VERSION 5.8 ;
BUSBITCHARS "[]" ;
DIVIDERCHAR "/" ;
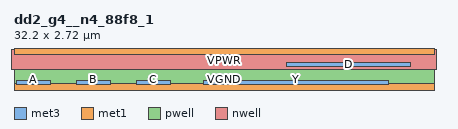
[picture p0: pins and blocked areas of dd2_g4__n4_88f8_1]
MACRO dd2_g4__n4_88f8_1
  CLASS CORE ;
  ORIGIN 0 0 ;
  SIZE 32.200 BY 2.720 ;
  SYMMETRY X Y ;
  SITE unithd ;
  PIN A
    DIRECTION INPUT ;
    USE SIGNAL ;
    ANTENNAGATEAREA 0.213000 ;
    PORT
      LAYER met3 ;
        RECT 0.185 0.175 2.815 0.505 ;
    END
  END A
  PIN B
    DIRECTION INPUT ;
    USE SIGNAL ;
    ANTENNAGATEAREA 0.213000 ;
    PORT
      LAYER met3 ;
        RECT 4.785 0.175 7.415 0.505 ;
    END
  END B
  PIN C
    DIRECTION INPUT ;
    USE SIGNAL ;
    ANTENNAGATEAREA 0.213000 ;
    PORT
      LAYER met3 ;
        RECT 9.385 0.175 12.015 0.505 ;
    END
  END C
  PIN D
    DIRECTION INPUT ;
    USE SIGNAL ;
    ANTENNAGATEAREA 0.213000 ;
    PORT
      LAYER met3 ;
        RECT 20.885 1.535 30.415 1.865 ;
    END
  END D
  PIN VGND
    DIRECTION INOUT ;
    USE GROUND ;
    SHAPE ABUTMENT ;
    PORT
      LAYER met1 ;
        RECT 0.000 -0.240 32.200 0.240 ;
    END
  END VGND
  PIN VNB
    DIRECTION INOUT ;
    USE GROUND ;
    PORT
      LAYER pwell ;
        RECT 0.000 0.000 32.200 1.305 ;
    END
  END VNB
  PIN VPB
    DIRECTION INOUT ;
    USE POWER ;
    PORT
      LAYER nwell ;
        RECT -0.190 1.305 32.390 2.910 ;
    END
  END VPB
  PIN VPWR
    DIRECTION INOUT ;
    USE POWER ;
    SHAPE ABUTMENT ;
    PORT
      LAYER met1 ;
        RECT 0.000 2.480 32.200 2.960 ;
    END
  END VPWR
  PIN Y
    DIRECTION OUTPUT ;
    USE SIGNAL ;
    ANTENNADIFFAREA 0.965600 ;
    PORT
      LAYER met3 ;
        RECT 14.560 0.175 28.690 0.505 ;
    END
  END Y
  OBS
    LAYER li1 ;
      RECT 0.000 -0.085 32.200 0.085 ;
      RECT 0.000 2.635 32.200 2.805 ;
      RECT 22.190 0.085 22.360 0.255 ;
      RECT 19.810 0.255 20.140 0.635 ;
      RECT 22.110 0.255 22.440 0.635 ;
      RECT 17.010 0.255 17.340 0.380 ;
      RECT 16.860 0.380 17.340 0.710 ;
      RECT 17.510 0.255 17.840 0.380 ;
      RECT 17.510 0.380 17.880 0.710 ;
      RECT 19.310 0.255 19.640 0.380 ;
      RECT 19.160 0.380 19.640 0.710 ;
      RECT 21.610 0.255 21.940 0.380 ;
      RECT 21.460 0.380 21.940 0.710 ;
      RECT 16.265 0.380 16.615 0.710 ;
      RECT 16.265 0.710 16.435 1.075 ;
      RECT 16.265 1.075 17.440 1.315 ;
      RECT 18.565 0.380 18.915 0.710 ;
      RECT 18.565 0.710 18.735 1.075 ;
      RECT 18.565 1.075 19.740 1.315 ;
      RECT 20.865 0.380 21.215 0.710 ;
      RECT 20.865 0.710 21.035 1.075 ;
      RECT 20.865 1.075 22.040 1.315 ;
      RECT 23.165 0.380 23.515 0.710 ;
      RECT 23.165 0.710 23.335 1.075 ;
      RECT 23.165 1.075 24.340 1.315 ;
      RECT 25.465 0.380 25.815 0.710 ;
      RECT 25.465 0.710 25.635 1.075 ;
      RECT 25.465 1.075 26.640 1.315 ;
      RECT 27.765 0.380 28.115 0.710 ;
      RECT 27.765 0.710 27.935 1.075 ;
      RECT 27.765 1.075 28.940 1.315 ;
      RECT 30.065 0.380 30.415 0.710 ;
      RECT 30.065 0.710 30.235 1.075 ;
      RECT 30.065 1.075 31.240 1.315 ;
      RECT 23.910 1.505 24.240 2.010 ;
      RECT 23.760 2.010 24.240 2.340 ;
      RECT 23.910 2.340 24.240 2.465 ;
      RECT 24.410 1.505 24.740 2.010 ;
      RECT 24.410 2.010 24.780 2.340 ;
      RECT 24.410 2.340 24.740 2.465 ;
      RECT 26.210 1.505 26.540 2.010 ;
      RECT 26.060 2.010 26.540 2.340 ;
      RECT 26.210 2.340 26.540 2.465 ;
      RECT 28.510 1.505 28.840 2.010 ;
      RECT 28.360 2.010 28.840 2.340 ;
      RECT 28.510 2.340 28.840 2.465 ;
      RECT 29.010 1.505 29.340 2.010 ;
      RECT 29.010 2.010 29.380 2.340 ;
      RECT 29.010 2.340 29.340 2.465 ;
      RECT 30.810 1.505 31.140 2.010 ;
      RECT 30.660 2.010 31.140 2.340 ;
      RECT 30.810 2.340 31.140 2.465 ;
      RECT 26.710 1.505 27.040 2.465 ;
      RECT 31.310 1.505 31.640 2.465 ;
      RECT 26.790 2.465 26.960 2.635 ;
      RECT 31.390 2.465 31.560 2.635 ;
      RECT 19.890 0.085 20.060 0.255 ;
      RECT 15.210 0.380 15.580 0.710 ;
      RECT 6.090 0.085 6.260 0.255 ;
      RECT 1.410 0.255 1.740 0.635 ;
      RECT 6.010 0.255 6.340 0.635 ;
      RECT 10.610 0.255 10.940 0.635 ;
      RECT 10.690 0.085 10.860 0.255 ;
      RECT 1.490 0.085 1.660 0.255 ;
      RECT 0.910 0.255 1.240 0.380 ;
      RECT 0.760 0.380 1.240 0.710 ;
      RECT 0.165 0.380 0.515 0.710 ;
      RECT 0.165 0.710 0.335 1.075 ;
      RECT 0.165 1.075 1.340 1.315 ;
      RECT 2.465 0.380 2.815 0.710 ;
      RECT 2.465 0.710 2.635 1.075 ;
      RECT 3.210 1.505 3.540 2.010 ;
      RECT 3.060 2.010 3.540 2.340 ;
      RECT 3.210 2.340 3.540 2.465 ;
      RECT 7.810 1.505 8.140 2.010 ;
      RECT 7.660 2.010 8.140 2.340 ;
      RECT 7.810 2.340 8.140 2.465 ;
      RECT 12.410 1.505 12.740 2.010 ;
      RECT 12.260 2.010 12.740 2.340 ;
      RECT 12.410 2.340 12.740 2.465 ;
      RECT 2.465 1.075 3.640 1.315 ;
      RECT 4.765 0.380 5.115 0.710 ;
      RECT 4.765 0.710 4.935 1.075 ;
      RECT 4.765 1.075 5.940 1.315 ;
      RECT 7.065 0.380 7.415 0.710 ;
      RECT 7.065 0.710 7.235 1.075 ;
      RECT 7.065 1.075 8.240 1.315 ;
      RECT 9.365 0.380 9.715 0.710 ;
      RECT 9.365 0.710 9.535 1.075 ;
      RECT 9.365 1.075 10.540 1.315 ;
      RECT 11.665 0.380 12.015 0.710 ;
      RECT 11.665 0.710 11.835 1.075 ;
      RECT 11.665 1.075 12.840 1.315 ;
      RECT 13.965 0.380 14.315 0.710 ;
      RECT 13.965 0.710 14.135 1.075 ;
      RECT 13.965 1.075 15.140 1.315 ;
      RECT 5.510 0.255 5.840 0.380 ;
      RECT 5.360 0.380 5.840 0.710 ;
      RECT 3.710 1.505 4.040 2.465 ;
      RECT 8.310 1.505 8.640 2.465 ;
      RECT 12.910 1.505 13.240 2.465 ;
      RECT 10.110 0.255 10.440 0.380 ;
      RECT 9.960 0.380 10.440 0.710 ;
      RECT 3.790 2.465 3.960 2.635 ;
      RECT 8.390 2.465 8.560 2.635 ;
      RECT 12.990 2.465 13.160 2.635 ;
      RECT 14.710 0.255 15.040 0.380 ;
      RECT 14.560 0.380 15.040 0.710 ;
      RECT 15.210 0.255 15.540 0.380 ;
    LAYER met1 ;
      RECT 0.185 0.380 0.515 0.710 ;
      RECT 2.485 0.380 2.815 0.710 ;
      RECT 4.785 0.380 5.115 0.710 ;
      RECT 5.360 0.380 5.690 0.710 ;
      RECT 7.085 0.380 7.415 0.710 ;
      RECT 9.385 0.380 9.715 0.710 ;
      RECT 9.960 0.380 10.290 0.710 ;
      RECT 11.685 0.380 12.015 0.710 ;
      RECT 14.560 0.380 14.890 0.710 ;
      RECT 15.250 0.380 15.580 0.710 ;
      RECT 16.285 0.380 16.615 0.710 ;
      RECT 16.860 0.380 17.190 0.710 ;
      RECT 17.550 0.380 17.880 0.710 ;
      RECT 18.585 0.380 18.915 0.710 ;
      RECT 19.160 0.380 19.490 0.710 ;
      RECT 20.885 0.380 21.215 0.710 ;
      RECT 21.460 0.380 21.790 0.710 ;
      RECT 25.485 0.380 25.815 0.710 ;
      RECT 27.785 0.380 28.115 0.710 ;
      RECT 30.085 0.380 30.415 0.710 ;
      RECT 0.760 0.380 1.090 0.710 ;
      RECT 13.985 0.380 14.315 0.710 ;
      RECT 23.185 0.380 23.515 0.710 ;
      RECT 0.765 0.710 1.085 0.850 ;
      RECT 3.065 0.790 3.385 0.850 ;
      RECT 13.990 0.710 14.310 0.850 ;
      RECT 23.190 0.710 23.510 0.850 ;
      RECT 0.760 0.850 23.515 0.990 ;
      RECT 0.765 0.990 1.085 1.050 ;
      RECT 3.065 0.990 3.385 1.050 ;
      RECT 13.990 0.990 14.310 1.050 ;
      RECT 23.190 0.990 23.510 1.050 ;
      RECT 24.455 0.790 24.775 0.850 ;
      RECT 26.065 0.790 26.385 0.850 ;
      RECT 24.450 0.850 26.390 0.990 ;
      RECT 24.455 0.990 24.775 1.050 ;
      RECT 26.065 0.990 26.385 1.050 ;
      RECT 29.055 0.790 29.375 0.850 ;
      RECT 30.665 0.790 30.985 0.850 ;
      RECT 29.050 0.850 30.990 0.990 ;
      RECT 29.055 0.990 29.375 1.050 ;
      RECT 30.665 0.990 30.985 1.050 ;
      RECT 5.365 1.230 5.685 1.290 ;
      RECT 7.665 1.230 7.985 1.290 ;
      RECT 16.290 1.230 16.610 1.290 ;
      RECT 25.490 1.230 25.810 1.290 ;
      RECT 5.360 1.290 25.815 1.430 ;
      RECT 5.365 1.430 5.685 1.490 ;
      RECT 7.665 1.430 7.985 1.490 ;
      RECT 16.290 1.430 16.610 1.490 ;
      RECT 25.490 1.430 25.810 1.490 ;
      RECT 3.060 2.010 3.390 2.340 ;
      RECT 7.660 2.010 7.990 2.340 ;
      RECT 9.965 1.670 10.285 1.730 ;
      RECT 12.265 1.670 12.585 1.730 ;
      RECT 18.590 1.670 18.910 1.730 ;
      RECT 27.790 1.670 28.110 1.730 ;
      RECT 9.960 1.730 28.115 1.870 ;
      RECT 9.965 1.870 10.285 1.930 ;
      RECT 18.590 1.870 18.910 1.930 ;
      RECT 27.790 1.870 28.110 1.930 ;
      RECT 12.265 1.870 12.585 2.010 ;
      RECT 12.260 2.010 12.590 2.340 ;
      RECT 23.760 2.010 24.090 2.340 ;
      RECT 24.450 2.010 24.780 2.340 ;
      RECT 26.060 2.010 26.390 2.340 ;
      RECT 28.360 2.010 28.690 2.340 ;
      RECT 29.050 2.010 29.380 2.340 ;
      RECT 30.660 2.010 30.990 2.340 ;
    LAYER met2 ;
      RECT 0.210 0.155 0.490 0.210 ;
      RECT 0.190 0.210 0.510 0.675 ;
      RECT 2.510 0.155 2.790 0.210 ;
      RECT 2.490 0.210 2.810 0.675 ;
      RECT 4.810 0.155 5.090 0.210 ;
      RECT 4.790 0.210 5.110 0.675 ;
      RECT 7.110 0.155 7.390 0.210 ;
      RECT 7.090 0.210 7.410 0.675 ;
      RECT 9.410 0.155 9.690 0.210 ;
      RECT 9.390 0.210 9.710 0.675 ;
      RECT 11.710 0.155 11.990 0.210 ;
      RECT 11.690 0.210 12.010 0.675 ;
      RECT 14.585 0.155 14.865 0.210 ;
      RECT 14.565 0.210 14.885 0.675 ;
      RECT 16.885 0.155 17.165 0.210 ;
      RECT 16.865 0.210 17.185 0.675 ;
      RECT 0.765 0.415 1.085 1.050 ;
      RECT 13.990 0.415 14.310 1.050 ;
      RECT 23.190 0.415 23.510 1.050 ;
      RECT 15.255 0.415 15.575 1.150 ;
      RECT 15.275 1.150 15.555 1.205 ;
      RECT 17.555 0.415 17.875 1.150 ;
      RECT 17.575 1.150 17.855 1.205 ;
      RECT 19.165 0.415 19.485 1.150 ;
      RECT 19.185 1.150 19.465 1.205 ;
      RECT 21.465 0.415 21.785 1.150 ;
      RECT 21.485 1.150 21.765 1.205 ;
      RECT 5.365 0.415 5.685 1.490 ;
      RECT 16.290 0.415 16.610 1.490 ;
      RECT 25.490 0.415 25.810 1.490 ;
      RECT 20.890 0.415 21.210 1.830 ;
      RECT 20.910 1.830 21.190 1.885 ;
      RECT 30.090 0.415 30.410 1.830 ;
      RECT 30.110 1.830 30.390 1.885 ;
      RECT 9.965 0.415 10.285 1.930 ;
      RECT 18.590 0.415 18.910 1.930 ;
      RECT 27.790 0.415 28.110 1.930 ;
      RECT 3.065 0.790 3.385 2.305 ;
      RECT 7.665 1.230 7.985 2.305 ;
      RECT 12.265 1.670 12.585 2.305 ;
      RECT 23.785 0.155 24.065 0.210 ;
      RECT 23.765 0.210 24.085 2.305 ;
      RECT 24.455 0.790 24.775 2.305 ;
      RECT 26.065 0.790 26.385 2.305 ;
      RECT 28.385 0.155 28.665 0.210 ;
      RECT 28.365 0.210 28.685 2.305 ;
      RECT 29.055 0.790 29.375 2.305 ;
      RECT 30.665 0.790 30.985 2.305 ;
    LAYER met3 ;
      RECT 15.250 0.855 21.790 1.185 ;
  END
END dd2_g4__n4_88f8_1
END LIBRARY
